VERSION 5.7 ;
  NOWIREEXTENSIONATPIN ON ;
  DIVIDERCHAR "/" ;
  BUSBITCHARS "[]" ;
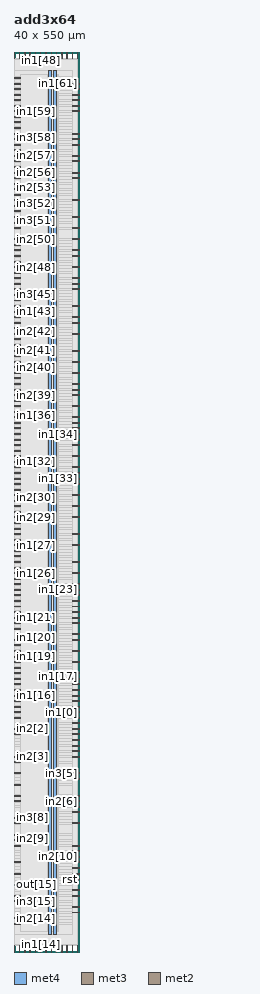
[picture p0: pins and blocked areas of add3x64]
MACRO add3x64
  CLASS BLOCK ;
  FOREIGN add3x64 ;
  ORIGIN 0.000 0.000 ;
  SIZE 40.000 BY 550.000 ;
  PIN VGND
    DIRECTION INOUT ;
    USE GROUND ;
    PORT
      LAYER met4 ;
        RECT 24.340 10.640 25.940 538.800 ;
    END
  END VGND
  PIN VPWR
    DIRECTION INOUT ;
    USE POWER ;
    PORT
      LAYER met4 ;
        RECT 21.040 10.640 22.640 538.800 ;
    END
  END VPWR
  PIN clk
    DIRECTION INPUT ;
    USE SIGNAL ;
    ANTENNAGATEAREA 1.286700 ;
    ANTENNADIFFAREA 0.434700 ;
    PORT
      LAYER met3 ;
        RECT 0.000 489.640 4.000 490.240 ;
    END
  END clk
  PIN in1[0]
    DIRECTION INPUT ;
    USE SIGNAL ;
    ANTENNAGATEAREA 0.631200 ;
    ANTENNADIFFAREA 0.434700 ;
    PORT
      LAYER met3 ;
        RECT 36.000 146.240 40.000 146.840 ;
    END
  END in1[0]
  PIN in1[10]
    DIRECTION INPUT ;
    USE SIGNAL ;
    ANTENNAGATEAREA 0.593700 ;
    ANTENNADIFFAREA 0.434700 ;
    PORT
      LAYER met2 ;
        RECT 19.410 0.000 19.690 4.000 ;
    END
  END in1[10]
  PIN in1[11]
    DIRECTION INPUT ;
    USE SIGNAL ;
    ANTENNAGATEAREA 0.631200 ;
    ANTENNADIFFAREA 0.434700 ;
    PORT
      LAYER met2 ;
        RECT 32.290 0.000 32.570 4.000 ;
    END
  END in1[11]
  PIN in1[12]
    DIRECTION INPUT ;
    USE SIGNAL ;
    ANTENNAGATEAREA 0.631200 ;
    ANTENNADIFFAREA 0.434700 ;
    PORT
      LAYER met2 ;
        RECT 38.730 0.000 39.010 4.000 ;
    END
  END in1[12]
  PIN in1[13]
    DIRECTION INPUT ;
    USE SIGNAL ;
    ANTENNAGATEAREA 0.560700 ;
    ANTENNADIFFAREA 0.434700 ;
    PORT
      LAYER met2 ;
        RECT 22.630 0.000 22.910 4.000 ;
    END
  END in1[13]
  PIN in1[14]
    DIRECTION INPUT ;
    USE SIGNAL ;
    ANTENNAGATEAREA 0.647700 ;
    ANTENNADIFFAREA 0.434700 ;
    PORT
      LAYER met2 ;
        RECT 16.190 0.000 16.470 4.000 ;
    END
  END in1[14]
  PIN in1[15]
    DIRECTION INPUT ;
    USE SIGNAL ;
    ANTENNAGATEAREA 0.560700 ;
    ANTENNADIFFAREA 0.434700 ;
    PORT
      LAYER met2 ;
        RECT 12.970 0.000 13.250 4.000 ;
    END
  END in1[15]
  PIN in1[16]
    DIRECTION INPUT ;
    USE SIGNAL ;
    ANTENNAGATEAREA 0.560700 ;
    ANTENNADIFFAREA 0.434700 ;
    PORT
      LAYER met3 ;
        RECT 0.000 156.440 4.000 157.040 ;
    END
  END in1[16]
  PIN in1[17]
    DIRECTION INPUT ;
    USE SIGNAL ;
    ANTENNAGATEAREA 0.647700 ;
    ANTENNADIFFAREA 0.434700 ;
    PORT
      LAYER met3 ;
        RECT 36.000 163.240 40.000 163.840 ;
    END
  END in1[17]
  PIN in1[18]
    DIRECTION INPUT ;
    USE SIGNAL ;
    ANTENNAGATEAREA 0.647700 ;
    ANTENNADIFFAREA 0.434700 ;
    PORT
      LAYER met3 ;
        RECT 0.000 170.040 4.000 170.640 ;
    END
  END in1[18]
  PIN in1[19]
    DIRECTION INPUT ;
    USE SIGNAL ;
    ANTENNAGATEAREA 0.560700 ;
    ANTENNADIFFAREA 0.434700 ;
    PORT
      LAYER met3 ;
        RECT 0.000 180.240 4.000 180.840 ;
    END
  END in1[19]
  PIN in1[1]
    DIRECTION INPUT ;
    USE SIGNAL ;
    ANTENNAGATEAREA 0.593700 ;
    ANTENNADIFFAREA 0.434700 ;
    PORT
      LAYER met3 ;
        RECT 0.000 146.240 4.000 146.840 ;
    END
  END in1[1]
  PIN in1[20]
    DIRECTION INPUT ;
    USE SIGNAL ;
    ANTENNAGATEAREA 0.647700 ;
    ANTENNADIFFAREA 0.434700 ;
    PORT
      LAYER met3 ;
        RECT 0.000 187.040 4.000 187.640 ;
    END
  END in1[20]
  PIN in1[21]
    DIRECTION INPUT ;
    USE SIGNAL ;
    ANTENNAGATEAREA 0.647700 ;
    ANTENNADIFFAREA 0.434700 ;
    PORT
      LAYER met3 ;
        RECT 0.000 204.040 4.000 204.640 ;
    END
  END in1[21]
  PIN in1[22]
    DIRECTION INPUT ;
    USE SIGNAL ;
    ANTENNAGATEAREA 0.560700 ;
    ANTENNADIFFAREA 0.434700 ;
    PORT
      LAYER met3 ;
        RECT 36.000 204.040 40.000 204.640 ;
    END
  END in1[22]
  PIN in1[23]
    DIRECTION INPUT ;
    USE SIGNAL ;
    ANTENNAGATEAREA 0.647700 ;
    ANTENNADIFFAREA 0.434700 ;
    PORT
      LAYER met3 ;
        RECT 36.000 221.040 40.000 221.640 ;
    END
  END in1[23]
  PIN in1[24]
    DIRECTION INPUT ;
    USE SIGNAL ;
    ANTENNAGATEAREA 0.631200 ;
    ANTENNADIFFAREA 0.434700 ;
    PORT
      LAYER met3 ;
        RECT 0.000 207.440 4.000 208.040 ;
    END
  END in1[24]
  PIN in1[25]
    DIRECTION INPUT ;
    USE SIGNAL ;
    ANTENNAGATEAREA 0.631200 ;
    ANTENNADIFFAREA 0.434700 ;
    PORT
      LAYER met3 ;
        RECT 0.000 221.040 4.000 221.640 ;
    END
  END in1[25]
  PIN in1[26]
    DIRECTION INPUT ;
    USE SIGNAL ;
    ANTENNAGATEAREA 0.647700 ;
    ANTENNADIFFAREA 0.434700 ;
    PORT
      LAYER met3 ;
        RECT 0.000 231.240 4.000 231.840 ;
    END
  END in1[26]
  PIN in1[27]
    DIRECTION INPUT ;
    USE SIGNAL ;
    ANTENNAGATEAREA 0.560700 ;
    ANTENNADIFFAREA 0.434700 ;
    PORT
      LAYER met3 ;
        RECT 0.000 248.240 4.000 248.840 ;
    END
  END in1[27]
  PIN in1[28]
    DIRECTION INPUT ;
    USE SIGNAL ;
    ANTENNAGATEAREA 0.560700 ;
    ANTENNADIFFAREA 0.434700 ;
    PORT
      LAYER met3 ;
        RECT 0.000 258.440 4.000 259.040 ;
    END
  END in1[28]
  PIN in1[29]
    DIRECTION INPUT ;
    USE SIGNAL ;
    ANTENNAGATEAREA 0.631200 ;
    ANTENNADIFFAREA 0.434700 ;
    PORT
      LAYER met3 ;
        RECT 0.000 261.840 4.000 262.440 ;
    END
  END in1[29]
  PIN in1[2]
    DIRECTION INPUT ;
    USE SIGNAL ;
    ANTENNAGATEAREA 0.647700 ;
    ANTENNADIFFAREA 0.434700 ;
    PORT
      LAYER met2 ;
        RECT 9.750 0.000 10.030 4.000 ;
    END
  END in1[2]
  PIN in1[30]
    DIRECTION INPUT ;
    USE SIGNAL ;
    ANTENNAGATEAREA 0.647700 ;
    ANTENNADIFFAREA 0.434700 ;
    PORT
      LAYER met3 ;
        RECT 0.000 285.640 4.000 286.240 ;
    END
  END in1[30]
  PIN in1[31]
    DIRECTION INPUT ;
    USE SIGNAL ;
    ANTENNAGATEAREA 0.631200 ;
    ANTENNADIFFAREA 0.434700 ;
    PORT
      LAYER met3 ;
        RECT 0.000 278.840 4.000 279.440 ;
    END
  END in1[31]
  PIN in1[32]
    DIRECTION INPUT ;
    USE SIGNAL ;
    ANTENNAGATEAREA 0.631200 ;
    ANTENNADIFFAREA 0.434700 ;
    PORT
      LAYER met3 ;
        RECT 0.000 299.240 4.000 299.840 ;
    END
  END in1[32]
  PIN in1[33]
    DIRECTION INPUT ;
    USE SIGNAL ;
    ANTENNAGATEAREA 0.631200 ;
    ANTENNADIFFAREA 0.434700 ;
    PORT
      LAYER met3 ;
        RECT 36.000 289.040 40.000 289.640 ;
    END
  END in1[33]
  PIN in1[34]
    DIRECTION INPUT ;
    USE SIGNAL ;
    ANTENNAGATEAREA 0.560700 ;
    ANTENNADIFFAREA 0.434700 ;
    PORT
      LAYER met3 ;
        RECT 36.000 316.240 40.000 316.840 ;
    END
  END in1[34]
  PIN in1[35]
    DIRECTION INPUT ;
    USE SIGNAL ;
    ANTENNAGATEAREA 0.647700 ;
    ANTENNADIFFAREA 0.434700 ;
    PORT
      LAYER met3 ;
        RECT 0.000 316.240 4.000 316.840 ;
    END
  END in1[35]
  PIN in1[36]
    DIRECTION INPUT ;
    USE SIGNAL ;
    ANTENNAGATEAREA 0.631200 ;
    ANTENNADIFFAREA 0.434700 ;
    PORT
      LAYER met3 ;
        RECT 0.000 323.040 4.000 323.640 ;
    END
  END in1[36]
  PIN in1[37]
    DIRECTION INPUT ;
    USE SIGNAL ;
    ANTENNAGATEAREA 0.631200 ;
    ANTENNADIFFAREA 0.434700 ;
    PORT
      LAYER met3 ;
        RECT 0.000 336.640 4.000 337.240 ;
    END
  END in1[37]
  PIN in1[38]
    DIRECTION INPUT ;
    USE SIGNAL ;
    ANTENNAGATEAREA 0.647700 ;
    ANTENNADIFFAREA 0.434700 ;
    PORT
      LAYER met3 ;
        RECT 36.000 346.840 40.000 347.440 ;
    END
  END in1[38]
  PIN in1[39]
    DIRECTION INPUT ;
    USE SIGNAL ;
    ANTENNAGATEAREA 0.631200 ;
    ANTENNADIFFAREA 0.434700 ;
    PORT
      LAYER met3 ;
        RECT 0.000 346.840 4.000 347.440 ;
    END
  END in1[39]
  PIN in1[3]
    DIRECTION INPUT ;
    USE SIGNAL ;
    ANTENNAGATEAREA 0.647700 ;
    ANTENNADIFFAREA 0.434700 ;
    PORT
      LAYER met2 ;
        RECT 0.090 0.000 0.370 4.000 ;
    END
  END in1[3]
  PIN in1[40]
    DIRECTION INPUT ;
    USE SIGNAL ;
    ANTENNAGATEAREA 0.631200 ;
    ANTENNADIFFAREA 0.434700 ;
    PORT
      LAYER met3 ;
        RECT 0.000 353.640 4.000 354.240 ;
    END
  END in1[40]
  PIN in1[41]
    DIRECTION INPUT ;
    USE SIGNAL ;
    ANTENNAGATEAREA 0.593700 ;
    ANTENNADIFFAREA 0.434700 ;
    PORT
      LAYER met3 ;
        RECT 0.000 363.840 4.000 364.440 ;
    END
  END in1[41]
  PIN in1[42]
    DIRECTION INPUT ;
    USE SIGNAL ;
    ANTENNAGATEAREA 0.631200 ;
    ANTENNADIFFAREA 0.434700 ;
    PORT
      LAYER met3 ;
        RECT 0.000 377.440 4.000 378.040 ;
    END
  END in1[42]
  PIN in1[43]
    DIRECTION INPUT ;
    USE SIGNAL ;
    ANTENNAGATEAREA 0.631200 ;
    ANTENNADIFFAREA 0.434700 ;
    PORT
      LAYER met3 ;
        RECT 0.000 391.040 4.000 391.640 ;
    END
  END in1[43]
  PIN in1[44]
    DIRECTION INPUT ;
    USE SIGNAL ;
    ANTENNAGATEAREA 0.631200 ;
    ANTENNADIFFAREA 0.434700 ;
    PORT
      LAYER met3 ;
        RECT 0.000 397.840 4.000 398.440 ;
    END
  END in1[44]
  PIN in1[45]
    DIRECTION INPUT ;
    USE SIGNAL ;
    ANTENNAGATEAREA 0.631200 ;
    ANTENNADIFFAREA 0.434700 ;
    PORT
      LAYER met3 ;
        RECT 0.000 411.440 4.000 412.040 ;
    END
  END in1[45]
  PIN in1[46]
    DIRECTION INPUT ;
    USE SIGNAL ;
    ANTENNAGATEAREA 0.593700 ;
    ANTENNADIFFAREA 0.434700 ;
    PORT
      LAYER met2 ;
        RECT 38.730 546.000 39.010 550.000 ;
    END
  END in1[46]
  PIN in1[47]
    DIRECTION INPUT ;
    USE SIGNAL ;
    ANTENNAGATEAREA 0.647700 ;
    ANTENNADIFFAREA 0.434700 ;
    PORT
      LAYER met2 ;
        RECT 32.290 546.000 32.570 550.000 ;
    END
  END in1[47]
  PIN in1[48]
    DIRECTION INPUT ;
    USE SIGNAL ;
    ANTENNAGATEAREA 0.647700 ;
    ANTENNADIFFAREA 0.434700 ;
    PORT
      LAYER met2 ;
        RECT 16.190 546.000 16.470 550.000 ;
    END
  END in1[48]
  PIN in1[49]
    DIRECTION INPUT ;
    USE SIGNAL ;
    ANTENNAGATEAREA 0.647700 ;
    ANTENNADIFFAREA 0.434700 ;
    PORT
      LAYER met2 ;
        RECT 35.510 546.000 35.790 550.000 ;
    END
  END in1[49]
  PIN in1[4]
    DIRECTION INPUT ;
    USE SIGNAL ;
    ANTENNAGATEAREA 0.647700 ;
    ANTENNADIFFAREA 0.434700 ;
    PORT
      LAYER met2 ;
        RECT 29.070 0.000 29.350 4.000 ;
    END
  END in1[4]
  PIN in1[50]
    DIRECTION INPUT ;
    USE SIGNAL ;
    ANTENNAGATEAREA 0.647700 ;
    ANTENNADIFFAREA 0.434700 ;
    PORT
      LAYER met2 ;
        RECT 12.970 546.000 13.250 550.000 ;
    END
  END in1[50]
  PIN in1[51]
    DIRECTION INPUT ;
    USE SIGNAL ;
    ANTENNAGATEAREA 0.647700 ;
    ANTENNADIFFAREA 0.434700 ;
    PORT
      LAYER met2 ;
        RECT 19.410 546.000 19.690 550.000 ;
    END
  END in1[51]
  PIN in1[52]
    DIRECTION INPUT ;
    USE SIGNAL ;
    ANTENNAGATEAREA 0.631200 ;
    ANTENNADIFFAREA 0.434700 ;
    PORT
      LAYER met2 ;
        RECT 9.750 546.000 10.030 550.000 ;
    END
  END in1[52]
  PIN in1[53]
    DIRECTION INPUT ;
    USE SIGNAL ;
    ANTENNAGATEAREA 0.560700 ;
    ANTENNADIFFAREA 0.434700 ;
    PORT
      LAYER met2 ;
        RECT 0.090 546.000 0.370 550.000 ;
    END
  END in1[53]
  PIN in1[54]
    DIRECTION INPUT ;
    USE SIGNAL ;
    ANTENNAGATEAREA 0.647700 ;
    ANTENNADIFFAREA 0.434700 ;
    PORT
      LAYER met2 ;
        RECT 25.850 546.000 26.130 550.000 ;
    END
  END in1[54]
  PIN in1[55]
    DIRECTION INPUT ;
    USE SIGNAL ;
    ANTENNAGATEAREA 0.631200 ;
    ANTENNADIFFAREA 0.434700 ;
    PORT
      LAYER met2 ;
        RECT 22.630 546.000 22.910 550.000 ;
    END
  END in1[55]
  PIN in1[56]
    DIRECTION INPUT ;
    USE SIGNAL ;
    ANTENNAGATEAREA 0.631200 ;
    ANTENNADIFFAREA 0.434700 ;
    PORT
      LAYER met2 ;
        RECT 3.310 546.000 3.590 550.000 ;
    END
  END in1[56]
  PIN in1[57]
    DIRECTION INPUT ;
    USE SIGNAL ;
    ANTENNAGATEAREA 0.631200 ;
    ANTENNADIFFAREA 0.434700 ;
    PORT
      LAYER met2 ;
        RECT 29.070 546.000 29.350 550.000 ;
    END
  END in1[57]
  PIN in1[58]
    DIRECTION INPUT ;
    USE SIGNAL ;
    ANTENNAGATEAREA 0.631200 ;
    ANTENNADIFFAREA 0.434700 ;
    PORT
      LAYER met2 ;
        RECT 6.530 546.000 6.810 550.000 ;
    END
  END in1[58]
  PIN in1[59]
    DIRECTION INPUT ;
    USE SIGNAL ;
    ANTENNAGATEAREA 0.631200 ;
    ANTENNADIFFAREA 0.434700 ;
    PORT
      LAYER met3 ;
        RECT 0.000 513.440 4.000 514.040 ;
    END
  END in1[59]
  PIN in1[5]
    DIRECTION INPUT ;
    USE SIGNAL ;
    ANTENNAGATEAREA 0.647700 ;
    ANTENNADIFFAREA 0.434700 ;
    PORT
      LAYER met2 ;
        RECT 35.510 0.000 35.790 4.000 ;
    END
  END in1[5]
  PIN in1[60]
    DIRECTION INPUT ;
    USE SIGNAL ;
    ANTENNAGATEAREA 0.631200 ;
    ANTENNADIFFAREA 0.434700 ;
    PORT
      LAYER met3 ;
        RECT 36.000 520.240 40.000 520.840 ;
    END
  END in1[60]
  PIN in1[61]
    DIRECTION INPUT ;
    USE SIGNAL ;
    ANTENNAGATEAREA 0.631200 ;
    ANTENNADIFFAREA 0.434700 ;
    PORT
      LAYER met3 ;
        RECT 36.000 530.440 40.000 531.040 ;
    END
  END in1[61]
  PIN in1[62]
    DIRECTION INPUT ;
    USE SIGNAL ;
    ANTENNAGATEAREA 0.631200 ;
    ANTENNADIFFAREA 0.434700 ;
    PORT
      LAYER met3 ;
        RECT 0.000 533.840 4.000 534.440 ;
    END
  END in1[62]
  PIN in1[63]
    DIRECTION INPUT ;
    USE SIGNAL ;
    ANTENNAGATEAREA 0.631200 ;
    ANTENNADIFFAREA 0.434700 ;
    PORT
      LAYER met3 ;
        RECT 0.000 523.640 4.000 524.240 ;
    END
  END in1[63]
  PIN in1[6]
    DIRECTION INPUT ;
    USE SIGNAL ;
    ANTENNAGATEAREA 0.647700 ;
    ANTENNADIFFAREA 0.434700 ;
    PORT
      LAYER met2 ;
        RECT 25.850 0.000 26.130 4.000 ;
    END
  END in1[6]
  PIN in1[7]
    DIRECTION INPUT ;
    USE SIGNAL ;
    ANTENNAGATEAREA 0.560700 ;
    ANTENNADIFFAREA 0.434700 ;
    PORT
      LAYER met2 ;
        RECT 3.310 0.000 3.590 4.000 ;
    END
  END in1[7]
  PIN in1[8]
    DIRECTION INPUT ;
    USE SIGNAL ;
    ANTENNAGATEAREA 0.560700 ;
    ANTENNADIFFAREA 0.434700 ;
    PORT
      LAYER met2 ;
        RECT 6.530 0.000 6.810 4.000 ;
    END
  END in1[8]
  PIN in1[9]
    DIRECTION INPUT ;
    USE SIGNAL ;
    ANTENNAGATEAREA 0.631200 ;
    ANTENNADIFFAREA 0.434700 ;
    PORT
      LAYER met3 ;
        RECT 0.000 71.440 4.000 72.040 ;
    END
  END in1[9]
  PIN in2[0]
    DIRECTION INPUT ;
    USE SIGNAL ;
    ANTENNAGATEAREA 0.631200 ;
    ANTENNADIFFAREA 0.434700 ;
    PORT
      LAYER met3 ;
        RECT 36.000 142.840 40.000 143.440 ;
    END
  END in2[0]
  PIN in2[10]
    DIRECTION INPUT ;
    USE SIGNAL ;
    ANTENNAGATEAREA 0.593700 ;
    ANTENNADIFFAREA 0.434700 ;
    PORT
      LAYER met3 ;
        RECT 36.000 57.840 40.000 58.440 ;
    END
  END in2[10]
  PIN in2[11]
    DIRECTION INPUT ;
    USE SIGNAL ;
    ANTENNAGATEAREA 0.631200 ;
    ANTENNADIFFAREA 0.434700 ;
    PORT
      LAYER met3 ;
        RECT 36.000 47.640 40.000 48.240 ;
    END
  END in2[11]
  PIN in2[12]
    DIRECTION INPUT ;
    USE SIGNAL ;
    ANTENNAGATEAREA 0.631200 ;
    ANTENNADIFFAREA 0.434700 ;
    PORT
      LAYER met3 ;
        RECT 36.000 37.440 40.000 38.040 ;
    END
  END in2[12]
  PIN in2[13]
    DIRECTION INPUT ;
    USE SIGNAL ;
    ANTENNAGATEAREA 0.560700 ;
    ANTENNADIFFAREA 0.434700 ;
    PORT
      LAYER met3 ;
        RECT 36.000 27.240 40.000 27.840 ;
    END
  END in2[13]
  PIN in2[14]
    DIRECTION INPUT ;
    USE SIGNAL ;
    ANTENNAGATEAREA 0.647700 ;
    ANTENNADIFFAREA 0.434700 ;
    PORT
      LAYER met3 ;
        RECT 0.000 20.440 4.000 21.040 ;
    END
  END in2[14]
  PIN in2[15]
    DIRECTION INPUT ;
    USE SIGNAL ;
    ANTENNAGATEAREA 0.560700 ;
    ANTENNADIFFAREA 0.434700 ;
    PORT
      LAYER met3 ;
        RECT 0.000 34.040 4.000 34.640 ;
    END
  END in2[15]
  PIN in2[16]
    DIRECTION INPUT ;
    USE SIGNAL ;
    ANTENNAGATEAREA 0.560700 ;
    ANTENNADIFFAREA 0.434700 ;
    PORT
      LAYER met3 ;
        RECT 0.000 159.840 4.000 160.440 ;
    END
  END in2[16]
  PIN in2[17]
    DIRECTION INPUT ;
    USE SIGNAL ;
    ANTENNAGATEAREA 0.647700 ;
    ANTENNADIFFAREA 0.434700 ;
    PORT
      LAYER met3 ;
        RECT 36.000 166.640 40.000 167.240 ;
    END
  END in2[17]
  PIN in2[18]
    DIRECTION INPUT ;
    USE SIGNAL ;
    ANTENNAGATEAREA 0.647700 ;
    ANTENNADIFFAREA 0.434700 ;
    PORT
      LAYER met3 ;
        RECT 0.000 166.640 4.000 167.240 ;
    END
  END in2[18]
  PIN in2[19]
    DIRECTION INPUT ;
    USE SIGNAL ;
    ANTENNAGATEAREA 0.560700 ;
    ANTENNADIFFAREA 0.434700 ;
    PORT
      LAYER met3 ;
        RECT 0.000 173.440 4.000 174.040 ;
    END
  END in2[19]
  PIN in2[1]
    DIRECTION INPUT ;
    USE SIGNAL ;
    ANTENNAGATEAREA 0.593700 ;
    ANTENNADIFFAREA 0.434700 ;
    PORT
      LAYER met3 ;
        RECT 0.000 142.840 4.000 143.440 ;
    END
  END in2[1]
  PIN in2[20]
    DIRECTION INPUT ;
    USE SIGNAL ;
    ANTENNAGATEAREA 0.647700 ;
    ANTENNADIFFAREA 0.434700 ;
    PORT
      LAYER met3 ;
        RECT 0.000 183.640 4.000 184.240 ;
    END
  END in2[20]
  PIN in2[21]
    DIRECTION INPUT ;
    USE SIGNAL ;
    ANTENNAGATEAREA 0.647700 ;
    ANTENNADIFFAREA 0.434700 ;
    PORT
      LAYER met3 ;
        RECT 0.000 197.240 4.000 197.840 ;
    END
  END in2[21]
  PIN in2[22]
    DIRECTION INPUT ;
    USE SIGNAL ;
    ANTENNAGATEAREA 0.560700 ;
    ANTENNADIFFAREA 0.434700 ;
    PORT
      LAYER met3 ;
        RECT 36.000 207.440 40.000 208.040 ;
    END
  END in2[22]
  PIN in2[23]
    DIRECTION INPUT ;
    USE SIGNAL ;
    ANTENNAGATEAREA 0.647700 ;
    ANTENNADIFFAREA 0.434700 ;
    PORT
      LAYER met3 ;
        RECT 36.000 217.640 40.000 218.240 ;
    END
  END in2[23]
  PIN in2[24]
    DIRECTION INPUT ;
    USE SIGNAL ;
    ANTENNAGATEAREA 0.631200 ;
    ANTENNADIFFAREA 0.434700 ;
    PORT
      LAYER met3 ;
        RECT 0.000 217.640 4.000 218.240 ;
    END
  END in2[24]
  PIN in2[25]
    DIRECTION INPUT ;
    USE SIGNAL ;
    ANTENNAGATEAREA 0.631200 ;
    ANTENNADIFFAREA 0.434700 ;
    PORT
      LAYER met3 ;
        RECT 0.000 227.840 4.000 228.440 ;
    END
  END in2[25]
  PIN in2[26]
    DIRECTION INPUT ;
    USE SIGNAL ;
    ANTENNAGATEAREA 0.647700 ;
    ANTENNADIFFAREA 0.434700 ;
    PORT
      LAYER met3 ;
        RECT 0.000 234.640 4.000 235.240 ;
    END
  END in2[26]
  PIN in2[27]
    DIRECTION INPUT ;
    USE SIGNAL ;
    ANTENNAGATEAREA 0.560700 ;
    ANTENNADIFFAREA 0.434700 ;
    PORT
      LAYER met3 ;
        RECT 0.000 244.840 4.000 245.440 ;
    END
  END in2[27]
  PIN in2[28]
    DIRECTION INPUT ;
    USE SIGNAL ;
    ANTENNAGATEAREA 0.631200 ;
    ANTENNADIFFAREA 0.434700 ;
    PORT
      LAYER met3 ;
        RECT 0.000 255.040 4.000 255.640 ;
    END
  END in2[28]
  PIN in2[29]
    DIRECTION INPUT ;
    USE SIGNAL ;
    ANTENNAGATEAREA 0.631200 ;
    ANTENNADIFFAREA 0.434700 ;
    PORT
      LAYER met3 ;
        RECT 0.000 265.240 4.000 265.840 ;
    END
  END in2[29]
  PIN in2[2]
    DIRECTION INPUT ;
    USE SIGNAL ;
    ANTENNAGATEAREA 0.631200 ;
    ANTENNADIFFAREA 0.434700 ;
    PORT
      LAYER met3 ;
        RECT 0.000 136.040 4.000 136.640 ;
    END
  END in2[2]
  PIN in2[30]
    DIRECTION INPUT ;
    USE SIGNAL ;
    ANTENNAGATEAREA 0.647700 ;
    ANTENNADIFFAREA 0.434700 ;
    PORT
      LAYER met3 ;
        RECT 0.000 282.240 4.000 282.840 ;
    END
  END in2[30]
  PIN in2[31]
    DIRECTION INPUT ;
    USE SIGNAL ;
    ANTENNAGATEAREA 0.631200 ;
    ANTENNADIFFAREA 0.434700 ;
    PORT
      LAYER met3 ;
        RECT 0.000 272.040 4.000 272.640 ;
    END
  END in2[31]
  PIN in2[32]
    DIRECTION INPUT ;
    USE SIGNAL ;
    ANTENNAGATEAREA 0.631200 ;
    ANTENNADIFFAREA 0.434700 ;
    PORT
      LAYER met3 ;
        RECT 0.000 292.440 4.000 293.040 ;
    END
  END in2[32]
  PIN in2[33]
    DIRECTION INPUT ;
    USE SIGNAL ;
    ANTENNAGATEAREA 0.631200 ;
    ANTENNADIFFAREA 0.434700 ;
    PORT
      LAYER met3 ;
        RECT 36.000 292.440 40.000 293.040 ;
    END
  END in2[33]
  PIN in2[34]
    DIRECTION INPUT ;
    USE SIGNAL ;
    ANTENNAGATEAREA 0.631200 ;
    ANTENNADIFFAREA 0.434700 ;
    PORT
      LAYER met3 ;
        RECT 36.000 309.440 40.000 310.040 ;
    END
  END in2[34]
  PIN in2[35]
    DIRECTION INPUT ;
    USE SIGNAL ;
    ANTENNAGATEAREA 0.647700 ;
    ANTENNADIFFAREA 0.434700 ;
    PORT
      LAYER met3 ;
        RECT 0.000 312.840 4.000 313.440 ;
    END
  END in2[35]
  PIN in2[36]
    DIRECTION INPUT ;
    USE SIGNAL ;
    ANTENNAGATEAREA 0.631200 ;
    ANTENNADIFFAREA 0.434700 ;
    PORT
      LAYER met3 ;
        RECT 0.000 326.440 4.000 327.040 ;
    END
  END in2[36]
  PIN in2[37]
    DIRECTION INPUT ;
    USE SIGNAL ;
    ANTENNAGATEAREA 0.631200 ;
    ANTENNADIFFAREA 0.434700 ;
    PORT
      LAYER met3 ;
        RECT 0.000 329.840 4.000 330.440 ;
    END
  END in2[37]
  PIN in2[38]
    DIRECTION INPUT ;
    USE SIGNAL ;
    ANTENNAGATEAREA 0.647700 ;
    ANTENNADIFFAREA 0.434700 ;
    PORT
      LAYER met3 ;
        RECT 36.000 343.440 40.000 344.040 ;
    END
  END in2[38]
  PIN in2[39]
    DIRECTION INPUT ;
    USE SIGNAL ;
    ANTENNAGATEAREA 0.631200 ;
    ANTENNADIFFAREA 0.434700 ;
    PORT
      LAYER met3 ;
        RECT 0.000 340.040 4.000 340.640 ;
    END
  END in2[39]
  PIN in2[3]
    DIRECTION INPUT ;
    USE SIGNAL ;
    ANTENNAGATEAREA 0.631200 ;
    ANTENNADIFFAREA 0.434700 ;
    PORT
      LAYER met3 ;
        RECT 0.000 119.040 4.000 119.640 ;
    END
  END in2[3]
  PIN in2[40]
    DIRECTION INPUT ;
    USE SIGNAL ;
    ANTENNAGATEAREA 0.631200 ;
    ANTENNADIFFAREA 0.434700 ;
    PORT
      LAYER met3 ;
        RECT 0.000 357.040 4.000 357.640 ;
    END
  END in2[40]
  PIN in2[41]
    DIRECTION INPUT ;
    USE SIGNAL ;
    ANTENNAGATEAREA 0.593700 ;
    ANTENNADIFFAREA 0.434700 ;
    PORT
      LAYER met3 ;
        RECT 0.000 367.240 4.000 367.840 ;
    END
  END in2[41]
  PIN in2[42]
    DIRECTION INPUT ;
    USE SIGNAL ;
    ANTENNAGATEAREA 0.631200 ;
    ANTENNADIFFAREA 0.434700 ;
    PORT
      LAYER met3 ;
        RECT 0.000 374.040 4.000 374.640 ;
    END
  END in2[42]
  PIN in2[43]
    DIRECTION INPUT ;
    USE SIGNAL ;
    ANTENNAGATEAREA 0.631200 ;
    ANTENNADIFFAREA 0.434700 ;
    PORT
      LAYER met3 ;
        RECT 0.000 384.240 4.000 384.840 ;
    END
  END in2[43]
  PIN in2[44]
    DIRECTION INPUT ;
    USE SIGNAL ;
    ANTENNAGATEAREA 0.631200 ;
    ANTENNADIFFAREA 0.434700 ;
    PORT
      LAYER met3 ;
        RECT 0.000 394.440 4.000 395.040 ;
    END
  END in2[44]
  PIN in2[45]
    DIRECTION INPUT ;
    USE SIGNAL ;
    ANTENNAGATEAREA 0.631200 ;
    ANTENNADIFFAREA 0.434700 ;
    PORT
      LAYER met3 ;
        RECT 0.000 404.640 4.000 405.240 ;
    END
  END in2[45]
  PIN in2[46]
    DIRECTION INPUT ;
    USE SIGNAL ;
    ANTENNAGATEAREA 0.560700 ;
    ANTENNADIFFAREA 0.434700 ;
    PORT
      LAYER met3 ;
        RECT 36.000 404.640 40.000 405.240 ;
    END
  END in2[46]
  PIN in2[47]
    DIRECTION INPUT ;
    USE SIGNAL ;
    ANTENNAGATEAREA 0.560700 ;
    ANTENNADIFFAREA 0.434700 ;
    PORT
      LAYER met3 ;
        RECT 0.000 421.640 4.000 422.240 ;
    END
  END in2[47]
  PIN in2[48]
    DIRECTION INPUT ;
    USE SIGNAL ;
    ANTENNAGATEAREA 0.631200 ;
    ANTENNADIFFAREA 0.434700 ;
    PORT
      LAYER met3 ;
        RECT 0.000 418.240 4.000 418.840 ;
    END
  END in2[48]
  PIN in2[49]
    DIRECTION INPUT ;
    USE SIGNAL ;
    ANTENNAGATEAREA 0.631200 ;
    ANTENNADIFFAREA 0.434700 ;
    PORT
      LAYER met3 ;
        RECT 0.000 428.440 4.000 429.040 ;
    END
  END in2[49]
  PIN in2[4]
    DIRECTION INPUT ;
    USE SIGNAL ;
    ANTENNAGATEAREA 0.631200 ;
    ANTENNADIFFAREA 0.434700 ;
    PORT
      LAYER met3 ;
        RECT 36.000 119.040 40.000 119.640 ;
    END
  END in2[4]
  PIN in2[50]
    DIRECTION INPUT ;
    USE SIGNAL ;
    ANTENNAGATEAREA 0.560700 ;
    ANTENNADIFFAREA 0.434700 ;
    PORT
      LAYER met3 ;
        RECT 0.000 435.240 4.000 435.840 ;
    END
  END in2[50]
  PIN in2[51]
    DIRECTION INPUT ;
    USE SIGNAL ;
    ANTENNAGATEAREA 0.647700 ;
    ANTENNADIFFAREA 0.434700 ;
    PORT
      LAYER met3 ;
        RECT 0.000 445.440 4.000 446.040 ;
    END
  END in2[51]
  PIN in2[52]
    DIRECTION INPUT ;
    USE SIGNAL ;
    ANTENNAGATEAREA 0.631200 ;
    ANTENNADIFFAREA 0.434700 ;
    PORT
      LAYER met3 ;
        RECT 0.000 448.840 4.000 449.440 ;
    END
  END in2[52]
  PIN in2[53]
    DIRECTION INPUT ;
    USE SIGNAL ;
    ANTENNAGATEAREA 0.631200 ;
    ANTENNADIFFAREA 0.434700 ;
    PORT
      LAYER met3 ;
        RECT 0.000 462.440 4.000 463.040 ;
    END
  END in2[53]
  PIN in2[54]
    DIRECTION INPUT ;
    USE SIGNAL ;
    ANTENNAGATEAREA 0.647700 ;
    ANTENNADIFFAREA 0.434700 ;
    PORT
      LAYER met3 ;
        RECT 0.000 465.840 4.000 466.440 ;
    END
  END in2[54]
  PIN in2[55]
    DIRECTION INPUT ;
    USE SIGNAL ;
    ANTENNAGATEAREA 0.631200 ;
    ANTENNADIFFAREA 0.434700 ;
    PORT
      LAYER met3 ;
        RECT 0.000 472.640 4.000 473.240 ;
    END
  END in2[55]
  PIN in2[56]
    DIRECTION INPUT ;
    USE SIGNAL ;
    ANTENNAGATEAREA 0.631200 ;
    ANTENNADIFFAREA 0.434700 ;
    PORT
      LAYER met3 ;
        RECT 0.000 476.040 4.000 476.640 ;
    END
  END in2[56]
  PIN in2[57]
    DIRECTION INPUT ;
    USE SIGNAL ;
    ANTENNAGATEAREA 0.631200 ;
    ANTENNADIFFAREA 0.434700 ;
    PORT
      LAYER met3 ;
        RECT 0.000 486.240 4.000 486.840 ;
    END
  END in2[57]
  PIN in2[58]
    DIRECTION INPUT ;
    USE SIGNAL ;
    ANTENNAGATEAREA 0.631200 ;
    ANTENNADIFFAREA 0.434700 ;
    PORT
      LAYER met3 ;
        RECT 0.000 496.440 4.000 497.040 ;
    END
  END in2[58]
  PIN in2[59]
    DIRECTION INPUT ;
    USE SIGNAL ;
    ANTENNAGATEAREA 0.631200 ;
    ANTENNADIFFAREA 0.434700 ;
    PORT
      LAYER met3 ;
        RECT 0.000 506.640 4.000 507.240 ;
    END
  END in2[59]
  PIN in2[5]
    DIRECTION INPUT ;
    USE SIGNAL ;
    ANTENNAGATEAREA 0.647700 ;
    ANTENNADIFFAREA 0.434700 ;
    PORT
      LAYER met3 ;
        RECT 36.000 105.440 40.000 106.040 ;
    END
  END in2[5]
  PIN in2[60]
    DIRECTION INPUT ;
    USE SIGNAL ;
    ANTENNAGATEAREA 0.631200 ;
    ANTENNADIFFAREA 0.434700 ;
    PORT
      LAYER met3 ;
        RECT 36.000 516.840 40.000 517.440 ;
    END
  END in2[60]
  PIN in2[61]
    DIRECTION INPUT ;
    USE SIGNAL ;
    ANTENNAGATEAREA 0.631200 ;
    ANTENNADIFFAREA 0.434700 ;
    PORT
      LAYER met3 ;
        RECT 36.000 523.640 40.000 524.240 ;
    END
  END in2[61]
  PIN in2[62]
    DIRECTION INPUT ;
    USE SIGNAL ;
    ANTENNAGATEAREA 0.631200 ;
    ANTENNADIFFAREA 0.434700 ;
    PORT
      LAYER met3 ;
        RECT 0.000 527.040 4.000 527.640 ;
    END
  END in2[62]
  PIN in2[63]
    DIRECTION INPUT ;
    USE SIGNAL ;
    ANTENNAGATEAREA 0.631200 ;
    ANTENNADIFFAREA 0.434700 ;
    PORT
      LAYER met3 ;
        RECT 0.000 516.840 4.000 517.440 ;
    END
  END in2[63]
  PIN in2[6]
    DIRECTION INPUT ;
    USE SIGNAL ;
    ANTENNAGATEAREA 0.560700 ;
    ANTENNADIFFAREA 0.434700 ;
    PORT
      LAYER met3 ;
        RECT 36.000 91.840 40.000 92.440 ;
    END
  END in2[6]
  PIN in2[7]
    DIRECTION INPUT ;
    USE SIGNAL ;
    ANTENNAGATEAREA 0.631200 ;
    ANTENNADIFFAREA 0.434700 ;
    PORT
      LAYER met3 ;
        RECT 0.000 91.840 4.000 92.440 ;
    END
  END in2[7]
  PIN in2[8]
    DIRECTION INPUT ;
    USE SIGNAL ;
    ANTENNAGATEAREA 0.631200 ;
    ANTENNADIFFAREA 0.434700 ;
    PORT
      LAYER met3 ;
        RECT 0.000 78.240 4.000 78.840 ;
    END
  END in2[8]
  PIN in2[9]
    DIRECTION INPUT ;
    USE SIGNAL ;
    ANTENNAGATEAREA 0.631200 ;
    ANTENNADIFFAREA 0.434700 ;
    PORT
      LAYER met3 ;
        RECT 0.000 64.640 4.000 65.240 ;
    END
  END in2[9]
  PIN in3[0]
    DIRECTION INPUT ;
    USE SIGNAL ;
    ANTENNAGATEAREA 0.631200 ;
    ANTENNADIFFAREA 0.434700 ;
    PORT
      LAYER met3 ;
        RECT 36.000 149.640 40.000 150.240 ;
    END
  END in3[0]
  PIN in3[10]
    DIRECTION INPUT ;
    USE SIGNAL ;
    ANTENNAGATEAREA 0.647700 ;
    ANTENNADIFFAREA 0.434700 ;
    PORT
      LAYER met3 ;
        RECT 36.000 61.240 40.000 61.840 ;
    END
  END in3[10]
  PIN in3[11]
    DIRECTION INPUT ;
    USE SIGNAL ;
    ANTENNAGATEAREA 0.631200 ;
    ANTENNADIFFAREA 0.434700 ;
    PORT
      LAYER met3 ;
        RECT 36.000 54.440 40.000 55.040 ;
    END
  END in3[11]
  PIN in3[12]
    DIRECTION INPUT ;
    USE SIGNAL ;
    ANTENNAGATEAREA 0.631200 ;
    ANTENNADIFFAREA 0.434700 ;
    PORT
      LAYER met3 ;
        RECT 36.000 34.040 40.000 34.640 ;
    END
  END in3[12]
  PIN in3[13]
    DIRECTION INPUT ;
    USE SIGNAL ;
    ANTENNAGATEAREA 0.631200 ;
    ANTENNADIFFAREA 0.434700 ;
    PORT
      LAYER met3 ;
        RECT 36.000 23.840 40.000 24.440 ;
    END
  END in3[13]
  PIN in3[14]
    DIRECTION INPUT ;
    USE SIGNAL ;
    ANTENNAGATEAREA 0.560700 ;
    ANTENNADIFFAREA 0.434700 ;
    PORT
      LAYER met3 ;
        RECT 0.000 17.040 4.000 17.640 ;
    END
  END in3[14]
  PIN in3[15]
    DIRECTION INPUT ;
    USE SIGNAL ;
    ANTENNAGATEAREA 0.631200 ;
    ANTENNADIFFAREA 0.434700 ;
    PORT
      LAYER met3 ;
        RECT 0.000 30.640 4.000 31.240 ;
    END
  END in3[15]
  PIN in3[16]
    DIRECTION INPUT ;
    USE SIGNAL ;
    ANTENNAGATEAREA 0.631200 ;
    ANTENNADIFFAREA 0.434700 ;
    PORT
      LAYER met3 ;
        RECT 0.000 163.240 4.000 163.840 ;
    END
  END in3[16]
  PIN in3[17]
    DIRECTION INPUT ;
    USE SIGNAL ;
    ANTENNAGATEAREA 0.631200 ;
    ANTENNADIFFAREA 0.434700 ;
    PORT
      LAYER met3 ;
        RECT 36.000 159.840 40.000 160.440 ;
    END
  END in3[17]
  PIN in3[18]
    DIRECTION INPUT ;
    USE SIGNAL ;
    ANTENNAGATEAREA 0.631200 ;
    ANTENNADIFFAREA 0.434700 ;
    PORT
      LAYER met3 ;
        RECT 36.000 170.040 40.000 170.640 ;
    END
  END in3[18]
  PIN in3[19]
    DIRECTION INPUT ;
    USE SIGNAL ;
    ANTENNAGATEAREA 0.631200 ;
    ANTENNADIFFAREA 0.434700 ;
    PORT
      LAYER met3 ;
        RECT 0.000 176.840 4.000 177.440 ;
    END
  END in3[19]
  PIN in3[1]
    DIRECTION INPUT ;
    USE SIGNAL ;
    ANTENNAGATEAREA 0.631200 ;
    ANTENNADIFFAREA 0.434700 ;
    PORT
      LAYER met3 ;
        RECT 0.000 149.640 4.000 150.240 ;
    END
  END in3[1]
  PIN in3[20]
    DIRECTION INPUT ;
    USE SIGNAL ;
    ANTENNAGATEAREA 0.631200 ;
    ANTENNADIFFAREA 0.434700 ;
    PORT
      LAYER met3 ;
        RECT 0.000 190.440 4.000 191.040 ;
    END
  END in3[20]
  PIN in3[21]
    DIRECTION INPUT ;
    USE SIGNAL ;
    ANTENNAGATEAREA 0.631200 ;
    ANTENNADIFFAREA 0.434700 ;
    PORT
      LAYER met3 ;
        RECT 0.000 200.640 4.000 201.240 ;
    END
  END in3[21]
  PIN in3[22]
    DIRECTION INPUT ;
    USE SIGNAL ;
    ANTENNAGATEAREA 0.631200 ;
    ANTENNADIFFAREA 0.434700 ;
    PORT
      LAYER met3 ;
        RECT 36.000 210.840 40.000 211.440 ;
    END
  END in3[22]
  PIN in3[23]
    DIRECTION INPUT ;
    USE SIGNAL ;
    ANTENNAGATEAREA 0.560700 ;
    ANTENNADIFFAREA 0.434700 ;
    PORT
      LAYER met3 ;
        RECT 36.000 214.240 40.000 214.840 ;
    END
  END in3[23]
  PIN in3[24]
    DIRECTION INPUT ;
    USE SIGNAL ;
    ANTENNAGATEAREA 0.631200 ;
    ANTENNADIFFAREA 0.434700 ;
    PORT
      LAYER met3 ;
        RECT 0.000 210.840 4.000 211.440 ;
    END
  END in3[24]
  PIN in3[25]
    DIRECTION INPUT ;
    USE SIGNAL ;
    ANTENNAGATEAREA 0.631200 ;
    ANTENNADIFFAREA 0.434700 ;
    PORT
      LAYER met3 ;
        RECT 0.000 224.440 4.000 225.040 ;
    END
  END in3[25]
  PIN in3[26]
    DIRECTION INPUT ;
    USE SIGNAL ;
    ANTENNAGATEAREA 0.631200 ;
    ANTENNADIFFAREA 0.434700 ;
    PORT
      LAYER met3 ;
        RECT 0.000 238.040 4.000 238.640 ;
    END
  END in3[26]
  PIN in3[27]
    DIRECTION INPUT ;
    USE SIGNAL ;
    ANTENNAGATEAREA 0.631200 ;
    ANTENNADIFFAREA 0.434700 ;
    PORT
      LAYER met3 ;
        RECT 0.000 241.440 4.000 242.040 ;
    END
  END in3[27]
  PIN in3[28]
    DIRECTION INPUT ;
    USE SIGNAL ;
    ANTENNAGATEAREA 0.631200 ;
    ANTENNADIFFAREA 0.434700 ;
    PORT
      LAYER met3 ;
        RECT 0.000 251.640 4.000 252.240 ;
    END
  END in3[28]
  PIN in3[29]
    DIRECTION INPUT ;
    USE SIGNAL ;
    ANTENNAGATEAREA 0.631200 ;
    ANTENNADIFFAREA 0.434700 ;
    PORT
      LAYER met3 ;
        RECT 0.000 268.640 4.000 269.240 ;
    END
  END in3[29]
  PIN in3[2]
    DIRECTION INPUT ;
    USE SIGNAL ;
    ANTENNAGATEAREA 0.631200 ;
    ANTENNADIFFAREA 0.434700 ;
    PORT
      LAYER met3 ;
        RECT 0.000 132.640 4.000 133.240 ;
    END
  END in3[2]
  PIN in3[30]
    DIRECTION INPUT ;
    USE SIGNAL ;
    ANTENNAGATEAREA 0.631200 ;
    ANTENNADIFFAREA 0.434700 ;
    PORT
      LAYER met3 ;
        RECT 0.000 295.840 4.000 296.440 ;
    END
  END in3[30]
  PIN in3[31]
    DIRECTION INPUT ;
    USE SIGNAL ;
    ANTENNAGATEAREA 0.631200 ;
    ANTENNADIFFAREA 0.434700 ;
    PORT
      LAYER met3 ;
        RECT 0.000 275.440 4.000 276.040 ;
    END
  END in3[31]
  PIN in3[32]
    DIRECTION INPUT ;
    USE SIGNAL ;
    ANTENNAGATEAREA 0.631200 ;
    ANTENNADIFFAREA 0.434700 ;
    PORT
      LAYER met3 ;
        RECT 0.000 289.040 4.000 289.640 ;
    END
  END in3[32]
  PIN in3[33]
    DIRECTION INPUT ;
    USE SIGNAL ;
    ANTENNAGATEAREA 0.631200 ;
    ANTENNADIFFAREA 0.434700 ;
    PORT
      LAYER met3 ;
        RECT 36.000 285.640 40.000 286.240 ;
    END
  END in3[33]
  PIN in3[34]
    DIRECTION INPUT ;
    USE SIGNAL ;
    ANTENNAGATEAREA 0.631200 ;
    ANTENNADIFFAREA 0.434700 ;
    PORT
      LAYER met3 ;
        RECT 36.000 312.840 40.000 313.440 ;
    END
  END in3[34]
  PIN in3[35]
    DIRECTION INPUT ;
    USE SIGNAL ;
    ANTENNAGATEAREA 0.631200 ;
    ANTENNADIFFAREA 0.434700 ;
    PORT
      LAYER met3 ;
        RECT 0.000 309.440 4.000 310.040 ;
    END
  END in3[35]
  PIN in3[36]
    DIRECTION INPUT ;
    USE SIGNAL ;
    ANTENNAGATEAREA 0.631200 ;
    ANTENNADIFFAREA 0.434700 ;
    PORT
      LAYER met3 ;
        RECT 0.000 319.640 4.000 320.240 ;
    END
  END in3[36]
  PIN in3[37]
    DIRECTION INPUT ;
    USE SIGNAL ;
    ANTENNAGATEAREA 0.631200 ;
    ANTENNADIFFAREA 0.434700 ;
    PORT
      LAYER met3 ;
        RECT 0.000 333.240 4.000 333.840 ;
    END
  END in3[37]
  PIN in3[38]
    DIRECTION INPUT ;
    USE SIGNAL ;
    ANTENNAGATEAREA 0.631200 ;
    ANTENNADIFFAREA 0.434700 ;
    PORT
      LAYER met3 ;
        RECT 36.000 340.040 40.000 340.640 ;
    END
  END in3[38]
  PIN in3[39]
    DIRECTION INPUT ;
    USE SIGNAL ;
    ANTENNAGATEAREA 0.631200 ;
    ANTENNADIFFAREA 0.434700 ;
    PORT
      LAYER met3 ;
        RECT 0.000 343.440 4.000 344.040 ;
    END
  END in3[39]
  PIN in3[3]
    DIRECTION INPUT ;
    USE SIGNAL ;
    ANTENNAGATEAREA 0.631200 ;
    ANTENNADIFFAREA 0.434700 ;
    PORT
      LAYER met3 ;
        RECT 0.000 115.640 4.000 116.240 ;
    END
  END in3[3]
  PIN in3[40]
    DIRECTION INPUT ;
    USE SIGNAL ;
    ANTENNAGATEAREA 0.631200 ;
    ANTENNADIFFAREA 0.434700 ;
    PORT
      LAYER met3 ;
        RECT 0.000 350.240 4.000 350.840 ;
    END
  END in3[40]
  PIN in3[41]
    DIRECTION INPUT ;
    USE SIGNAL ;
    ANTENNAGATEAREA 0.631200 ;
    ANTENNADIFFAREA 0.434700 ;
    PORT
      LAYER met3 ;
        RECT 0.000 360.440 4.000 361.040 ;
    END
  END in3[41]
  PIN in3[42]
    DIRECTION INPUT ;
    USE SIGNAL ;
    ANTENNAGATEAREA 0.631200 ;
    ANTENNADIFFAREA 0.434700 ;
    PORT
      LAYER met3 ;
        RECT 0.000 370.640 4.000 371.240 ;
    END
  END in3[42]
  PIN in3[43]
    DIRECTION INPUT ;
    USE SIGNAL ;
    ANTENNAGATEAREA 0.631200 ;
    ANTENNADIFFAREA 0.434700 ;
    PORT
      LAYER met3 ;
        RECT 0.000 380.840 4.000 381.440 ;
    END
  END in3[43]
  PIN in3[44]
    DIRECTION INPUT ;
    USE SIGNAL ;
    ANTENNAGATEAREA 0.631200 ;
    ANTENNADIFFAREA 0.434700 ;
    PORT
      LAYER met3 ;
        RECT 0.000 387.640 4.000 388.240 ;
    END
  END in3[44]
  PIN in3[45]
    DIRECTION INPUT ;
    USE SIGNAL ;
    ANTENNAGATEAREA 0.560700 ;
    ANTENNADIFFAREA 0.434700 ;
    PORT
      LAYER met3 ;
        RECT 0.000 401.240 4.000 401.840 ;
    END
  END in3[45]
  PIN in3[46]
    DIRECTION INPUT ;
    USE SIGNAL ;
    ANTENNAGATEAREA 0.631200 ;
    ANTENNADIFFAREA 0.434700 ;
    PORT
      LAYER met3 ;
        RECT 36.000 408.040 40.000 408.640 ;
    END
  END in3[46]
  PIN in3[47]
    DIRECTION INPUT ;
    USE SIGNAL ;
    ANTENNAGATEAREA 0.631200 ;
    ANTENNADIFFAREA 0.434700 ;
    PORT
      LAYER met3 ;
        RECT 0.000 408.040 4.000 408.640 ;
    END
  END in3[47]
  PIN in3[48]
    DIRECTION INPUT ;
    USE SIGNAL ;
    ANTENNAGATEAREA 0.631200 ;
    ANTENNADIFFAREA 0.434700 ;
    PORT
      LAYER met3 ;
        RECT 0.000 414.840 4.000 415.440 ;
    END
  END in3[48]
  PIN in3[49]
    DIRECTION INPUT ;
    USE SIGNAL ;
    ANTENNAGATEAREA 0.631200 ;
    ANTENNADIFFAREA 0.434700 ;
    PORT
      LAYER met3 ;
        RECT 0.000 425.040 4.000 425.640 ;
    END
  END in3[49]
  PIN in3[4]
    DIRECTION INPUT ;
    USE SIGNAL ;
    ANTENNAGATEAREA 0.647700 ;
    ANTENNADIFFAREA 0.434700 ;
    PORT
      LAYER met3 ;
        RECT 36.000 122.440 40.000 123.040 ;
    END
  END in3[4]
  PIN in3[50]
    DIRECTION INPUT ;
    USE SIGNAL ;
    ANTENNAGATEAREA 0.631200 ;
    ANTENNADIFFAREA 0.434700 ;
    PORT
      LAYER met3 ;
        RECT 0.000 431.840 4.000 432.440 ;
    END
  END in3[50]
  PIN in3[51]
    DIRECTION INPUT ;
    USE SIGNAL ;
    ANTENNAGATEAREA 0.631200 ;
    ANTENNADIFFAREA 0.434700 ;
    PORT
      LAYER met3 ;
        RECT 0.000 442.040 4.000 442.640 ;
    END
  END in3[51]
  PIN in3[52]
    DIRECTION INPUT ;
    USE SIGNAL ;
    ANTENNAGATEAREA 0.631200 ;
    ANTENNADIFFAREA 0.434700 ;
    PORT
      LAYER met3 ;
        RECT 0.000 452.240 4.000 452.840 ;
    END
  END in3[52]
  PIN in3[53]
    DIRECTION INPUT ;
    USE SIGNAL ;
    ANTENNAGATEAREA 0.631200 ;
    ANTENNADIFFAREA 0.434700 ;
    PORT
      LAYER met3 ;
        RECT 0.000 459.040 4.000 459.640 ;
    END
  END in3[53]
  PIN in3[54]
    DIRECTION INPUT ;
    USE SIGNAL ;
    ANTENNAGATEAREA 0.631200 ;
    ANTENNADIFFAREA 0.434700 ;
    PORT
      LAYER met3 ;
        RECT 0.000 455.640 4.000 456.240 ;
    END
  END in3[54]
  PIN in3[55]
    DIRECTION INPUT ;
    USE SIGNAL ;
    ANTENNAGATEAREA 0.631200 ;
    ANTENNADIFFAREA 0.434700 ;
    PORT
      LAYER met3 ;
        RECT 0.000 469.240 4.000 469.840 ;
    END
  END in3[55]
  PIN in3[56]
    DIRECTION INPUT ;
    USE SIGNAL ;
    ANTENNAGATEAREA 0.631200 ;
    ANTENNADIFFAREA 0.434700 ;
    PORT
      LAYER met3 ;
        RECT 0.000 479.440 4.000 480.040 ;
    END
  END in3[56]
  PIN in3[57]
    DIRECTION INPUT ;
    USE SIGNAL ;
    ANTENNAGATEAREA 0.631200 ;
    ANTENNADIFFAREA 0.434700 ;
    PORT
      LAYER met3 ;
        RECT 0.000 482.840 4.000 483.440 ;
    END
  END in3[57]
  PIN in3[58]
    DIRECTION INPUT ;
    USE SIGNAL ;
    ANTENNAGATEAREA 0.631200 ;
    ANTENNADIFFAREA 0.434700 ;
    PORT
      LAYER met3 ;
        RECT 0.000 493.040 4.000 493.640 ;
    END
  END in3[58]
  PIN in3[59]
    DIRECTION INPUT ;
    USE SIGNAL ;
    ANTENNAGATEAREA 0.631200 ;
    ANTENNADIFFAREA 0.434700 ;
    PORT
      LAYER met3 ;
        RECT 0.000 510.040 4.000 510.640 ;
    END
  END in3[59]
  PIN in3[5]
    DIRECTION INPUT ;
    USE SIGNAL ;
    ANTENNAGATEAREA 0.631200 ;
    ANTENNADIFFAREA 0.434700 ;
    PORT
      LAYER met3 ;
        RECT 36.000 108.840 40.000 109.440 ;
    END
  END in3[5]
  PIN in3[60]
    DIRECTION INPUT ;
    USE SIGNAL ;
    ANTENNAGATEAREA 0.631200 ;
    ANTENNADIFFAREA 0.434700 ;
    PORT
      LAYER met3 ;
        RECT 36.000 513.440 40.000 514.040 ;
    END
  END in3[60]
  PIN in3[61]
    DIRECTION INPUT ;
    USE SIGNAL ;
    ANTENNAGATEAREA 0.631200 ;
    ANTENNADIFFAREA 0.434700 ;
    PORT
      LAYER met3 ;
        RECT 36.000 527.040 40.000 527.640 ;
    END
  END in3[61]
  PIN in3[62]
    DIRECTION INPUT ;
    USE SIGNAL ;
    ANTENNAGATEAREA 0.631200 ;
    ANTENNADIFFAREA 0.434700 ;
    PORT
      LAYER met3 ;
        RECT 0.000 530.440 4.000 531.040 ;
    END
  END in3[62]
  PIN in3[63]
    DIRECTION INPUT ;
    USE SIGNAL ;
    ANTENNAGATEAREA 0.631200 ;
    ANTENNADIFFAREA 0.434700 ;
    PORT
      LAYER met3 ;
        RECT 0.000 520.240 4.000 520.840 ;
    END
  END in3[63]
  PIN in3[6]
    DIRECTION INPUT ;
    USE SIGNAL ;
    ANTENNAGATEAREA 0.560700 ;
    ANTENNADIFFAREA 0.434700 ;
    PORT
      LAYER met3 ;
        RECT 36.000 95.240 40.000 95.840 ;
    END
  END in3[6]
  PIN in3[7]
    DIRECTION INPUT ;
    USE SIGNAL ;
    ANTENNAGATEAREA 0.631200 ;
    ANTENNADIFFAREA 0.434700 ;
    PORT
      LAYER met3 ;
        RECT 0.000 95.240 4.000 95.840 ;
    END
  END in3[7]
  PIN in3[8]
    DIRECTION INPUT ;
    USE SIGNAL ;
    ANTENNAGATEAREA 0.631200 ;
    ANTENNADIFFAREA 0.434700 ;
    PORT
      LAYER met3 ;
        RECT 0.000 81.640 4.000 82.240 ;
    END
  END in3[8]
  PIN in3[9]
    DIRECTION INPUT ;
    USE SIGNAL ;
    ANTENNAGATEAREA 0.631200 ;
    ANTENNADIFFAREA 0.434700 ;
    PORT
      LAYER met3 ;
        RECT 0.000 68.040 4.000 68.640 ;
    END
  END in3[9]
  PIN out[0]
    DIRECTION OUTPUT ;
    USE SIGNAL ;
    ANTENNADIFFAREA 0.445500 ;
    PORT
      LAYER met3 ;
        RECT 36.000 153.040 40.000 153.640 ;
    END
  END out[0]
  PIN out[10]
    DIRECTION OUTPUT ;
    USE SIGNAL ;
    ANTENNADIFFAREA 0.445500 ;
    PORT
      LAYER met3 ;
        RECT 36.000 78.240 40.000 78.840 ;
    END
  END out[10]
  PIN out[11]
    DIRECTION OUTPUT ;
    USE SIGNAL ;
    ANTENNADIFFAREA 0.445500 ;
    PORT
      LAYER met3 ;
        RECT 36.000 64.640 40.000 65.240 ;
    END
  END out[11]
  PIN out[12]
    DIRECTION OUTPUT ;
    USE SIGNAL ;
    ANTENNADIFFAREA 0.445500 ;
    PORT
      LAYER met3 ;
        RECT 0.000 54.440 4.000 55.040 ;
    END
  END out[12]
  PIN out[13]
    DIRECTION OUTPUT ;
    USE SIGNAL ;
    ANTENNADIFFAREA 0.445500 ;
    PORT
      LAYER met3 ;
        RECT 0.000 47.640 4.000 48.240 ;
    END
  END out[13]
  PIN out[14]
    DIRECTION OUTPUT ;
    USE SIGNAL ;
    ANTENNADIFFAREA 0.445500 ;
    PORT
      LAYER met3 ;
        RECT 36.000 51.040 40.000 51.640 ;
    END
  END out[14]
  PIN out[15]
    DIRECTION OUTPUT ;
    USE SIGNAL ;
    ANTENNADIFFAREA 0.445500 ;
    PORT
      LAYER met3 ;
        RECT 0.000 40.840 4.000 41.440 ;
    END
  END out[15]
  PIN out[16]
    DIRECTION OUTPUT ;
    USE SIGNAL ;
    ANTENNADIFFAREA 0.445500 ;
    PORT
      LAYER met3 ;
        RECT 36.000 156.440 40.000 157.040 ;
    END
  END out[16]
  PIN out[17]
    DIRECTION OUTPUT ;
    USE SIGNAL ;
    ANTENNADIFFAREA 0.445500 ;
    PORT
      LAYER met3 ;
        RECT 0.000 153.040 4.000 153.640 ;
    END
  END out[17]
  PIN out[18]
    DIRECTION OUTPUT ;
    USE SIGNAL ;
    ANTENNADIFFAREA 0.445500 ;
    PORT
      LAYER met3 ;
        RECT 36.000 176.840 40.000 177.440 ;
    END
  END out[18]
  PIN out[19]
    DIRECTION OUTPUT ;
    USE SIGNAL ;
    ANTENNADIFFAREA 0.445500 ;
    PORT
      LAYER met3 ;
        RECT 36.000 183.640 40.000 184.240 ;
    END
  END out[19]
  PIN out[1]
    DIRECTION OUTPUT ;
    USE SIGNAL ;
    ANTENNADIFFAREA 0.445500 ;
    PORT
      LAYER met3 ;
        RECT 36.000 139.440 40.000 140.040 ;
    END
  END out[1]
  PIN out[20]
    DIRECTION OUTPUT ;
    USE SIGNAL ;
    ANTENNADIFFAREA 0.445500 ;
    PORT
      LAYER met3 ;
        RECT 36.000 190.440 40.000 191.040 ;
    END
  END out[20]
  PIN out[21]
    DIRECTION OUTPUT ;
    USE SIGNAL ;
    ANTENNADIFFAREA 0.445500 ;
    PORT
      LAYER met3 ;
        RECT 36.000 193.840 40.000 194.440 ;
    END
  END out[21]
  PIN out[22]
    DIRECTION OUTPUT ;
    USE SIGNAL ;
    ANTENNADIFFAREA 0.445500 ;
    PORT
      LAYER met3 ;
        RECT 36.000 200.640 40.000 201.240 ;
    END
  END out[22]
  PIN out[23]
    DIRECTION OUTPUT ;
    USE SIGNAL ;
    ANTENNADIFFAREA 0.445500 ;
    PORT
      LAYER met3 ;
        RECT 0.000 214.240 4.000 214.840 ;
    END
  END out[23]
  PIN out[24]
    DIRECTION OUTPUT ;
    USE SIGNAL ;
    ANTENNADIFFAREA 0.445500 ;
    PORT
      LAYER met3 ;
        RECT 36.000 224.440 40.000 225.040 ;
    END
  END out[24]
  PIN out[25]
    DIRECTION OUTPUT ;
    USE SIGNAL ;
    ANTENNADIFFAREA 0.445500 ;
    PORT
      LAYER met3 ;
        RECT 36.000 231.240 40.000 231.840 ;
    END
  END out[25]
  PIN out[26]
    DIRECTION OUTPUT ;
    USE SIGNAL ;
    ANTENNADIFFAREA 0.445500 ;
    PORT
      LAYER met3 ;
        RECT 36.000 238.040 40.000 238.640 ;
    END
  END out[26]
  PIN out[27]
    DIRECTION OUTPUT ;
    USE SIGNAL ;
    ANTENNADIFFAREA 0.445500 ;
    PORT
      LAYER met3 ;
        RECT 36.000 248.240 40.000 248.840 ;
    END
  END out[27]
  PIN out[28]
    DIRECTION OUTPUT ;
    USE SIGNAL ;
    ANTENNADIFFAREA 0.445500 ;
    PORT
      LAYER met3 ;
        RECT 36.000 255.040 40.000 255.640 ;
    END
  END out[28]
  PIN out[29]
    DIRECTION OUTPUT ;
    USE SIGNAL ;
    ANTENNADIFFAREA 0.445500 ;
    PORT
      LAYER met3 ;
        RECT 36.000 265.240 40.000 265.840 ;
    END
  END out[29]
  PIN out[2]
    DIRECTION OUTPUT ;
    USE SIGNAL ;
    ANTENNADIFFAREA 0.445500 ;
    PORT
      LAYER met3 ;
        RECT 36.000 132.640 40.000 133.240 ;
    END
  END out[2]
  PIN out[30]
    DIRECTION OUTPUT ;
    USE SIGNAL ;
    ANTENNADIFFAREA 0.445500 ;
    PORT
      LAYER met3 ;
        RECT 36.000 272.040 40.000 272.640 ;
    END
  END out[30]
  PIN out[31]
    DIRECTION OUTPUT ;
    USE SIGNAL ;
    ANTENNADIFFAREA 0.445500 ;
    PORT
      LAYER met3 ;
        RECT 36.000 278.840 40.000 279.440 ;
    END
  END out[31]
  PIN out[32]
    DIRECTION OUTPUT ;
    USE SIGNAL ;
    ANTENNADIFFAREA 0.445500 ;
    PORT
      LAYER met3 ;
        RECT 0.000 302.640 4.000 303.240 ;
    END
  END out[32]
  PIN out[33]
    DIRECTION OUTPUT ;
    USE SIGNAL ;
    ANTENNADIFFAREA 0.445500 ;
    PORT
      LAYER met3 ;
        RECT 36.000 295.840 40.000 296.440 ;
    END
  END out[33]
  PIN out[34]
    DIRECTION OUTPUT ;
    USE SIGNAL ;
    ANTENNADIFFAREA 0.445500 ;
    PORT
      LAYER met3 ;
        RECT 36.000 302.640 40.000 303.240 ;
    END
  END out[34]
  PIN out[35]
    DIRECTION OUTPUT ;
    USE SIGNAL ;
    ANTENNADIFFAREA 0.445500 ;
    PORT
      LAYER met3 ;
        RECT 0.000 306.040 4.000 306.640 ;
    END
  END out[35]
  PIN out[36]
    DIRECTION OUTPUT ;
    USE SIGNAL ;
    ANTENNADIFFAREA 0.445500 ;
    PORT
      LAYER met3 ;
        RECT 36.000 319.640 40.000 320.240 ;
    END
  END out[36]
  PIN out[37]
    DIRECTION OUTPUT ;
    USE SIGNAL ;
    ANTENNADIFFAREA 0.445500 ;
    PORT
      LAYER met3 ;
        RECT 36.000 323.040 40.000 323.640 ;
    END
  END out[37]
  PIN out[38]
    DIRECTION OUTPUT ;
    USE SIGNAL ;
    ANTENNADIFFAREA 0.445500 ;
    PORT
      LAYER met3 ;
        RECT 36.000 326.440 40.000 327.040 ;
    END
  END out[38]
  PIN out[39]
    DIRECTION OUTPUT ;
    USE SIGNAL ;
    ANTENNADIFFAREA 0.445500 ;
    PORT
      LAYER met3 ;
        RECT 36.000 333.240 40.000 333.840 ;
    END
  END out[39]
  PIN out[3]
    DIRECTION OUTPUT ;
    USE SIGNAL ;
    ANTENNADIFFAREA 0.445500 ;
    PORT
      LAYER met3 ;
        RECT 36.000 136.040 40.000 136.640 ;
    END
  END out[3]
  PIN out[40]
    DIRECTION OUTPUT ;
    USE SIGNAL ;
    ANTENNADIFFAREA 0.445500 ;
    PORT
      LAYER met3 ;
        RECT 36.000 353.640 40.000 354.240 ;
    END
  END out[40]
  PIN out[41]
    DIRECTION OUTPUT ;
    USE SIGNAL ;
    ANTENNADIFFAREA 0.445500 ;
    PORT
      LAYER met3 ;
        RECT 36.000 360.440 40.000 361.040 ;
    END
  END out[41]
  PIN out[42]
    DIRECTION OUTPUT ;
    USE SIGNAL ;
    ANTENNADIFFAREA 0.445500 ;
    PORT
      LAYER met3 ;
        RECT 36.000 367.240 40.000 367.840 ;
    END
  END out[42]
  PIN out[43]
    DIRECTION OUTPUT ;
    USE SIGNAL ;
    ANTENNADIFFAREA 0.445500 ;
    PORT
      LAYER met3 ;
        RECT 36.000 377.440 40.000 378.040 ;
    END
  END out[43]
  PIN out[44]
    DIRECTION OUTPUT ;
    USE SIGNAL ;
    ANTENNADIFFAREA 0.445500 ;
    PORT
      LAYER met3 ;
        RECT 36.000 384.240 40.000 384.840 ;
    END
  END out[44]
  PIN out[45]
    DIRECTION OUTPUT ;
    USE SIGNAL ;
    ANTENNADIFFAREA 0.445500 ;
    PORT
      LAYER met3 ;
        RECT 36.000 387.640 40.000 388.240 ;
    END
  END out[45]
  PIN out[46]
    DIRECTION OUTPUT ;
    USE SIGNAL ;
    ANTENNADIFFAREA 0.445500 ;
    PORT
      LAYER met3 ;
        RECT 36.000 394.440 40.000 395.040 ;
    END
  END out[46]
  PIN out[47]
    DIRECTION OUTPUT ;
    USE SIGNAL ;
    ANTENNADIFFAREA 0.445500 ;
    PORT
      LAYER met3 ;
        RECT 36.000 411.440 40.000 412.040 ;
    END
  END out[47]
  PIN out[48]
    DIRECTION OUTPUT ;
    USE SIGNAL ;
    ANTENNADIFFAREA 0.445500 ;
    PORT
      LAYER met3 ;
        RECT 36.000 418.240 40.000 418.840 ;
    END
  END out[48]
  PIN out[49]
    DIRECTION OUTPUT ;
    USE SIGNAL ;
    ANTENNADIFFAREA 0.445500 ;
    PORT
      LAYER met3 ;
        RECT 36.000 425.040 40.000 425.640 ;
    END
  END out[49]
  PIN out[4]
    DIRECTION OUTPUT ;
    USE SIGNAL ;
    ANTENNADIFFAREA 0.445500 ;
    PORT
      LAYER met3 ;
        RECT 36.000 125.840 40.000 126.440 ;
    END
  END out[4]
  PIN out[50]
    DIRECTION OUTPUT ;
    USE SIGNAL ;
    ANTENNADIFFAREA 0.445500 ;
    PORT
      LAYER met3 ;
        RECT 36.000 428.440 40.000 429.040 ;
    END
  END out[50]
  PIN out[51]
    DIRECTION OUTPUT ;
    USE SIGNAL ;
    ANTENNADIFFAREA 0.445500 ;
    PORT
      LAYER met3 ;
        RECT 36.000 435.240 40.000 435.840 ;
    END
  END out[51]
  PIN out[52]
    DIRECTION OUTPUT ;
    USE SIGNAL ;
    ANTENNADIFFAREA 0.445500 ;
    PORT
      LAYER met3 ;
        RECT 36.000 442.040 40.000 442.640 ;
    END
  END out[52]
  PIN out[53]
    DIRECTION OUTPUT ;
    USE SIGNAL ;
    ANTENNADIFFAREA 0.445500 ;
    PORT
      LAYER met3 ;
        RECT 36.000 448.840 40.000 449.440 ;
    END
  END out[53]
  PIN out[54]
    DIRECTION OUTPUT ;
    USE SIGNAL ;
    ANTENNADIFFAREA 0.445500 ;
    PORT
      LAYER met3 ;
        RECT 36.000 459.040 40.000 459.640 ;
    END
  END out[54]
  PIN out[55]
    DIRECTION OUTPUT ;
    USE SIGNAL ;
    ANTENNADIFFAREA 0.445500 ;
    PORT
      LAYER met3 ;
        RECT 36.000 472.640 40.000 473.240 ;
    END
  END out[55]
  PIN out[56]
    DIRECTION OUTPUT ;
    USE SIGNAL ;
    ANTENNADIFFAREA 0.445500 ;
    PORT
      LAYER met3 ;
        RECT 36.000 476.040 40.000 476.640 ;
    END
  END out[56]
  PIN out[57]
    DIRECTION OUTPUT ;
    USE SIGNAL ;
    ANTENNADIFFAREA 0.445500 ;
    PORT
      LAYER met3 ;
        RECT 36.000 482.840 40.000 483.440 ;
    END
  END out[57]
  PIN out[58]
    DIRECTION OUTPUT ;
    USE SIGNAL ;
    ANTENNADIFFAREA 0.445500 ;
    PORT
      LAYER met3 ;
        RECT 36.000 486.240 40.000 486.840 ;
    END
  END out[58]
  PIN out[59]
    DIRECTION OUTPUT ;
    USE SIGNAL ;
    ANTENNADIFFAREA 0.445500 ;
    PORT
      LAYER met3 ;
        RECT 36.000 496.440 40.000 497.040 ;
    END
  END out[59]
  PIN out[5]
    DIRECTION OUTPUT ;
    USE SIGNAL ;
    ANTENNADIFFAREA 0.445500 ;
    PORT
      LAYER met3 ;
        RECT 36.000 129.240 40.000 129.840 ;
    END
  END out[5]
  PIN out[60]
    DIRECTION OUTPUT ;
    USE SIGNAL ;
    ANTENNADIFFAREA 0.445500 ;
    PORT
      LAYER met3 ;
        RECT 36.000 493.040 40.000 493.640 ;
    END
  END out[60]
  PIN out[61]
    DIRECTION OUTPUT ;
    USE SIGNAL ;
    ANTENNADIFFAREA 0.445500 ;
    PORT
      LAYER met3 ;
        RECT 36.000 499.840 40.000 500.440 ;
    END
  END out[61]
  PIN out[62]
    DIRECTION OUTPUT ;
    USE SIGNAL ;
    ANTENNADIFFAREA 0.445500 ;
    PORT
      LAYER met3 ;
        RECT 0.000 499.840 4.000 500.440 ;
    END
  END out[62]
  PIN out[63]
    DIRECTION OUTPUT ;
    USE SIGNAL ;
    ANTENNADIFFAREA 0.445500 ;
    PORT
      LAYER met3 ;
        RECT 0.000 503.240 4.000 503.840 ;
    END
  END out[63]
  PIN out[6]
    DIRECTION OUTPUT ;
    USE SIGNAL ;
    ANTENNADIFFAREA 0.445500 ;
    PORT
      LAYER met3 ;
        RECT 0.000 108.840 4.000 109.440 ;
    END
  END out[6]
  PIN out[7]
    DIRECTION OUTPUT ;
    USE SIGNAL ;
    ANTENNADIFFAREA 0.445500 ;
    PORT
      LAYER met3 ;
        RECT 0.000 102.040 4.000 102.640 ;
    END
  END out[7]
  PIN out[8]
    DIRECTION OUTPUT ;
    USE SIGNAL ;
    ANTENNADIFFAREA 0.445500 ;
    PORT
      LAYER met3 ;
        RECT 36.000 88.440 40.000 89.040 ;
    END
  END out[8]
  PIN out[9]
    DIRECTION OUTPUT ;
    USE SIGNAL ;
    ANTENNADIFFAREA 0.445500 ;
    PORT
      LAYER met3 ;
        RECT 36.000 85.040 40.000 85.640 ;
    END
  END out[9]
  PIN rst
    DIRECTION INPUT ;
    USE SIGNAL ;
    ANTENNAGATEAREA 0.631200 ;
    ANTENNADIFFAREA 0.434700 ;
    PORT
      LAYER met3 ;
        RECT 36.000 44.240 40.000 44.840 ;
    END
  END rst
  OBS
      LAYER nwell ;
        RECT 5.330 10.795 34.230 538.645 ;
      LAYER li1 ;
        RECT 5.520 10.795 34.040 538.645 ;
      LAYER met1 ;
        RECT 0.070 6.160 39.030 538.800 ;
      LAYER met2 ;
        RECT 0.650 545.720 3.030 546.000 ;
        RECT 3.870 545.720 6.250 546.000 ;
        RECT 7.090 545.720 9.470 546.000 ;
        RECT 10.310 545.720 12.690 546.000 ;
        RECT 13.530 545.720 15.910 546.000 ;
        RECT 16.750 545.720 19.130 546.000 ;
        RECT 19.970 545.720 22.350 546.000 ;
        RECT 23.190 545.720 25.570 546.000 ;
        RECT 26.410 545.720 28.790 546.000 ;
        RECT 29.630 545.720 32.010 546.000 ;
        RECT 32.850 545.720 35.230 546.000 ;
        RECT 36.070 545.720 38.450 546.000 ;
        RECT 0.100 4.280 39.000 545.720 ;
        RECT 0.650 4.000 3.030 4.280 ;
        RECT 3.870 4.000 6.250 4.280 ;
        RECT 7.090 4.000 9.470 4.280 ;
        RECT 10.310 4.000 12.690 4.280 ;
        RECT 13.530 4.000 15.910 4.280 ;
        RECT 16.750 4.000 19.130 4.280 ;
        RECT 19.970 4.000 22.350 4.280 ;
        RECT 23.190 4.000 25.570 4.280 ;
        RECT 26.410 4.000 28.790 4.280 ;
        RECT 29.630 4.000 32.010 4.280 ;
        RECT 32.850 4.000 35.230 4.280 ;
        RECT 36.070 4.000 38.450 4.280 ;
      LAYER met3 ;
        RECT 0.525 534.840 36.000 538.725 ;
        RECT 4.400 533.440 36.000 534.840 ;
        RECT 0.525 531.440 36.000 533.440 ;
        RECT 4.400 530.040 35.600 531.440 ;
        RECT 0.525 528.040 36.000 530.040 ;
        RECT 4.400 526.640 35.600 528.040 ;
        RECT 0.525 524.640 36.000 526.640 ;
        RECT 4.400 523.240 35.600 524.640 ;
        RECT 0.525 521.240 36.000 523.240 ;
        RECT 4.400 519.840 35.600 521.240 ;
        RECT 0.525 517.840 36.000 519.840 ;
        RECT 4.400 516.440 35.600 517.840 ;
        RECT 0.525 514.440 36.000 516.440 ;
        RECT 4.400 513.040 35.600 514.440 ;
        RECT 0.525 511.040 36.000 513.040 ;
        RECT 4.400 509.640 36.000 511.040 ;
        RECT 0.525 507.640 36.000 509.640 ;
        RECT 4.400 506.240 36.000 507.640 ;
        RECT 0.525 504.240 36.000 506.240 ;
        RECT 4.400 502.840 36.000 504.240 ;
        RECT 0.525 500.840 36.000 502.840 ;
        RECT 4.400 499.440 35.600 500.840 ;
        RECT 0.525 497.440 36.000 499.440 ;
        RECT 4.400 496.040 35.600 497.440 ;
        RECT 0.525 494.040 36.000 496.040 ;
        RECT 4.400 492.640 35.600 494.040 ;
        RECT 0.525 490.640 36.000 492.640 ;
        RECT 4.400 489.240 36.000 490.640 ;
        RECT 0.525 487.240 36.000 489.240 ;
        RECT 4.400 485.840 35.600 487.240 ;
        RECT 0.525 483.840 36.000 485.840 ;
        RECT 4.400 482.440 35.600 483.840 ;
        RECT 0.525 480.440 36.000 482.440 ;
        RECT 4.400 479.040 36.000 480.440 ;
        RECT 0.525 477.040 36.000 479.040 ;
        RECT 4.400 475.640 35.600 477.040 ;
        RECT 0.525 473.640 36.000 475.640 ;
        RECT 4.400 472.240 35.600 473.640 ;
        RECT 0.525 470.240 36.000 472.240 ;
        RECT 4.400 468.840 36.000 470.240 ;
        RECT 0.525 466.840 36.000 468.840 ;
        RECT 4.400 465.440 36.000 466.840 ;
        RECT 0.525 463.440 36.000 465.440 ;
        RECT 4.400 462.040 36.000 463.440 ;
        RECT 0.525 460.040 36.000 462.040 ;
        RECT 4.400 458.640 35.600 460.040 ;
        RECT 0.525 456.640 36.000 458.640 ;
        RECT 4.400 455.240 36.000 456.640 ;
        RECT 0.525 453.240 36.000 455.240 ;
        RECT 4.400 451.840 36.000 453.240 ;
        RECT 0.525 449.840 36.000 451.840 ;
        RECT 4.400 448.440 35.600 449.840 ;
        RECT 0.525 446.440 36.000 448.440 ;
        RECT 4.400 445.040 36.000 446.440 ;
        RECT 0.525 443.040 36.000 445.040 ;
        RECT 4.400 441.640 35.600 443.040 ;
        RECT 0.525 436.240 36.000 441.640 ;
        RECT 4.400 434.840 35.600 436.240 ;
        RECT 0.525 432.840 36.000 434.840 ;
        RECT 4.400 431.440 36.000 432.840 ;
        RECT 0.525 429.440 36.000 431.440 ;
        RECT 4.400 428.040 35.600 429.440 ;
        RECT 0.525 426.040 36.000 428.040 ;
        RECT 4.400 424.640 35.600 426.040 ;
        RECT 0.525 422.640 36.000 424.640 ;
        RECT 4.400 421.240 36.000 422.640 ;
        RECT 0.525 419.240 36.000 421.240 ;
        RECT 4.400 417.840 35.600 419.240 ;
        RECT 0.525 415.840 36.000 417.840 ;
        RECT 4.400 414.440 36.000 415.840 ;
        RECT 0.525 412.440 36.000 414.440 ;
        RECT 4.400 411.040 35.600 412.440 ;
        RECT 0.525 409.040 36.000 411.040 ;
        RECT 4.400 407.640 35.600 409.040 ;
        RECT 0.525 405.640 36.000 407.640 ;
        RECT 4.400 404.240 35.600 405.640 ;
        RECT 0.525 402.240 36.000 404.240 ;
        RECT 4.400 400.840 36.000 402.240 ;
        RECT 0.525 398.840 36.000 400.840 ;
        RECT 4.400 397.440 36.000 398.840 ;
        RECT 0.525 395.440 36.000 397.440 ;
        RECT 4.400 394.040 35.600 395.440 ;
        RECT 0.525 392.040 36.000 394.040 ;
        RECT 4.400 390.640 36.000 392.040 ;
        RECT 0.525 388.640 36.000 390.640 ;
        RECT 4.400 387.240 35.600 388.640 ;
        RECT 0.525 385.240 36.000 387.240 ;
        RECT 4.400 383.840 35.600 385.240 ;
        RECT 0.525 381.840 36.000 383.840 ;
        RECT 4.400 380.440 36.000 381.840 ;
        RECT 0.525 378.440 36.000 380.440 ;
        RECT 4.400 377.040 35.600 378.440 ;
        RECT 0.525 375.040 36.000 377.040 ;
        RECT 4.400 373.640 36.000 375.040 ;
        RECT 0.525 371.640 36.000 373.640 ;
        RECT 4.400 370.240 36.000 371.640 ;
        RECT 0.525 368.240 36.000 370.240 ;
        RECT 4.400 366.840 35.600 368.240 ;
        RECT 0.525 364.840 36.000 366.840 ;
        RECT 4.400 363.440 36.000 364.840 ;
        RECT 0.525 361.440 36.000 363.440 ;
        RECT 4.400 360.040 35.600 361.440 ;
        RECT 0.525 358.040 36.000 360.040 ;
        RECT 4.400 356.640 36.000 358.040 ;
        RECT 0.525 354.640 36.000 356.640 ;
        RECT 4.400 353.240 35.600 354.640 ;
        RECT 0.525 351.240 36.000 353.240 ;
        RECT 4.400 349.840 36.000 351.240 ;
        RECT 0.525 347.840 36.000 349.840 ;
        RECT 4.400 346.440 35.600 347.840 ;
        RECT 0.525 344.440 36.000 346.440 ;
        RECT 4.400 343.040 35.600 344.440 ;
        RECT 0.525 341.040 36.000 343.040 ;
        RECT 4.400 339.640 35.600 341.040 ;
        RECT 0.525 337.640 36.000 339.640 ;
        RECT 4.400 336.240 36.000 337.640 ;
        RECT 0.525 334.240 36.000 336.240 ;
        RECT 4.400 332.840 35.600 334.240 ;
        RECT 0.525 330.840 36.000 332.840 ;
        RECT 4.400 329.440 36.000 330.840 ;
        RECT 0.525 327.440 36.000 329.440 ;
        RECT 4.400 326.040 35.600 327.440 ;
        RECT 0.525 324.040 36.000 326.040 ;
        RECT 4.400 322.640 35.600 324.040 ;
        RECT 0.525 320.640 36.000 322.640 ;
        RECT 4.400 319.240 35.600 320.640 ;
        RECT 0.525 317.240 36.000 319.240 ;
        RECT 4.400 315.840 35.600 317.240 ;
        RECT 0.525 313.840 36.000 315.840 ;
        RECT 4.400 312.440 35.600 313.840 ;
        RECT 0.525 310.440 36.000 312.440 ;
        RECT 4.400 309.040 35.600 310.440 ;
        RECT 0.525 307.040 36.000 309.040 ;
        RECT 4.400 305.640 36.000 307.040 ;
        RECT 0.525 303.640 36.000 305.640 ;
        RECT 4.400 302.240 35.600 303.640 ;
        RECT 0.525 300.240 36.000 302.240 ;
        RECT 4.400 298.840 36.000 300.240 ;
        RECT 0.525 296.840 36.000 298.840 ;
        RECT 4.400 295.440 35.600 296.840 ;
        RECT 0.525 293.440 36.000 295.440 ;
        RECT 4.400 292.040 35.600 293.440 ;
        RECT 0.525 290.040 36.000 292.040 ;
        RECT 4.400 288.640 35.600 290.040 ;
        RECT 0.525 286.640 36.000 288.640 ;
        RECT 4.400 285.240 35.600 286.640 ;
        RECT 0.525 283.240 36.000 285.240 ;
        RECT 4.400 281.840 36.000 283.240 ;
        RECT 0.525 279.840 36.000 281.840 ;
        RECT 4.400 278.440 35.600 279.840 ;
        RECT 0.525 276.440 36.000 278.440 ;
        RECT 4.400 275.040 36.000 276.440 ;
        RECT 0.525 273.040 36.000 275.040 ;
        RECT 4.400 271.640 35.600 273.040 ;
        RECT 0.525 269.640 36.000 271.640 ;
        RECT 4.400 268.240 36.000 269.640 ;
        RECT 0.525 266.240 36.000 268.240 ;
        RECT 4.400 264.840 35.600 266.240 ;
        RECT 0.525 262.840 36.000 264.840 ;
        RECT 4.400 261.440 36.000 262.840 ;
        RECT 0.525 259.440 36.000 261.440 ;
        RECT 4.400 258.040 36.000 259.440 ;
        RECT 0.525 256.040 36.000 258.040 ;
        RECT 4.400 254.640 35.600 256.040 ;
        RECT 0.525 252.640 36.000 254.640 ;
        RECT 4.400 251.240 36.000 252.640 ;
        RECT 0.525 249.240 36.000 251.240 ;
        RECT 4.400 247.840 35.600 249.240 ;
        RECT 0.525 245.840 36.000 247.840 ;
        RECT 4.400 244.440 36.000 245.840 ;
        RECT 0.525 242.440 36.000 244.440 ;
        RECT 4.400 241.040 36.000 242.440 ;
        RECT 0.525 239.040 36.000 241.040 ;
        RECT 4.400 237.640 35.600 239.040 ;
        RECT 0.525 235.640 36.000 237.640 ;
        RECT 4.400 234.240 36.000 235.640 ;
        RECT 0.525 232.240 36.000 234.240 ;
        RECT 4.400 230.840 35.600 232.240 ;
        RECT 0.525 228.840 36.000 230.840 ;
        RECT 4.400 227.440 36.000 228.840 ;
        RECT 0.525 225.440 36.000 227.440 ;
        RECT 4.400 224.040 35.600 225.440 ;
        RECT 0.525 222.040 36.000 224.040 ;
        RECT 4.400 220.640 35.600 222.040 ;
        RECT 0.525 218.640 36.000 220.640 ;
        RECT 4.400 217.240 35.600 218.640 ;
        RECT 0.525 215.240 36.000 217.240 ;
        RECT 4.400 213.840 35.600 215.240 ;
        RECT 0.525 211.840 36.000 213.840 ;
        RECT 4.400 210.440 35.600 211.840 ;
        RECT 0.525 208.440 36.000 210.440 ;
        RECT 4.400 207.040 35.600 208.440 ;
        RECT 0.525 205.040 36.000 207.040 ;
        RECT 4.400 203.640 35.600 205.040 ;
        RECT 0.525 201.640 36.000 203.640 ;
        RECT 4.400 200.240 35.600 201.640 ;
        RECT 0.525 198.240 36.000 200.240 ;
        RECT 4.400 196.840 36.000 198.240 ;
        RECT 0.525 194.840 36.000 196.840 ;
        RECT 0.525 193.440 35.600 194.840 ;
        RECT 0.525 191.440 36.000 193.440 ;
        RECT 4.400 190.040 35.600 191.440 ;
        RECT 0.525 188.040 36.000 190.040 ;
        RECT 4.400 186.640 36.000 188.040 ;
        RECT 0.525 184.640 36.000 186.640 ;
        RECT 4.400 183.240 35.600 184.640 ;
        RECT 0.525 181.240 36.000 183.240 ;
        RECT 4.400 179.840 36.000 181.240 ;
        RECT 0.525 177.840 36.000 179.840 ;
        RECT 4.400 176.440 35.600 177.840 ;
        RECT 0.525 174.440 36.000 176.440 ;
        RECT 4.400 173.040 36.000 174.440 ;
        RECT 0.525 171.040 36.000 173.040 ;
        RECT 4.400 169.640 35.600 171.040 ;
        RECT 0.525 167.640 36.000 169.640 ;
        RECT 4.400 166.240 35.600 167.640 ;
        RECT 0.525 164.240 36.000 166.240 ;
        RECT 4.400 162.840 35.600 164.240 ;
        RECT 0.525 160.840 36.000 162.840 ;
        RECT 4.400 159.440 35.600 160.840 ;
        RECT 0.525 157.440 36.000 159.440 ;
        RECT 4.400 156.040 35.600 157.440 ;
        RECT 0.525 154.040 36.000 156.040 ;
        RECT 4.400 152.640 35.600 154.040 ;
        RECT 0.525 150.640 36.000 152.640 ;
        RECT 4.400 149.240 35.600 150.640 ;
        RECT 0.525 147.240 36.000 149.240 ;
        RECT 4.400 145.840 35.600 147.240 ;
        RECT 0.525 143.840 36.000 145.840 ;
        RECT 4.400 142.440 35.600 143.840 ;
        RECT 0.525 140.440 36.000 142.440 ;
        RECT 0.525 139.040 35.600 140.440 ;
        RECT 0.525 137.040 36.000 139.040 ;
        RECT 4.400 135.640 35.600 137.040 ;
        RECT 0.525 133.640 36.000 135.640 ;
        RECT 4.400 132.240 35.600 133.640 ;
        RECT 0.525 130.240 36.000 132.240 ;
        RECT 0.525 128.840 35.600 130.240 ;
        RECT 0.525 126.840 36.000 128.840 ;
        RECT 0.525 125.440 35.600 126.840 ;
        RECT 0.525 123.440 36.000 125.440 ;
        RECT 0.525 122.040 35.600 123.440 ;
        RECT 0.525 120.040 36.000 122.040 ;
        RECT 4.400 118.640 35.600 120.040 ;
        RECT 0.525 116.640 36.000 118.640 ;
        RECT 4.400 115.240 36.000 116.640 ;
        RECT 0.525 109.840 36.000 115.240 ;
        RECT 4.400 108.440 35.600 109.840 ;
        RECT 0.525 106.440 36.000 108.440 ;
        RECT 0.525 105.040 35.600 106.440 ;
        RECT 0.525 103.040 36.000 105.040 ;
        RECT 4.400 101.640 36.000 103.040 ;
        RECT 0.525 96.240 36.000 101.640 ;
        RECT 4.400 94.840 35.600 96.240 ;
        RECT 0.525 92.840 36.000 94.840 ;
        RECT 4.400 91.440 35.600 92.840 ;
        RECT 0.525 89.440 36.000 91.440 ;
        RECT 0.525 88.040 35.600 89.440 ;
        RECT 0.525 86.040 36.000 88.040 ;
        RECT 0.525 84.640 35.600 86.040 ;
        RECT 0.525 82.640 36.000 84.640 ;
        RECT 4.400 81.240 36.000 82.640 ;
        RECT 0.525 79.240 36.000 81.240 ;
        RECT 4.400 77.840 35.600 79.240 ;
        RECT 0.525 72.440 36.000 77.840 ;
        RECT 4.400 71.040 36.000 72.440 ;
        RECT 0.525 69.040 36.000 71.040 ;
        RECT 4.400 67.640 36.000 69.040 ;
        RECT 0.525 65.640 36.000 67.640 ;
        RECT 4.400 64.240 35.600 65.640 ;
        RECT 0.525 62.240 36.000 64.240 ;
        RECT 0.525 60.840 35.600 62.240 ;
        RECT 0.525 58.840 36.000 60.840 ;
        RECT 0.525 57.440 35.600 58.840 ;
        RECT 0.525 55.440 36.000 57.440 ;
        RECT 4.400 54.040 35.600 55.440 ;
        RECT 0.525 52.040 36.000 54.040 ;
        RECT 0.525 50.640 35.600 52.040 ;
        RECT 0.525 48.640 36.000 50.640 ;
        RECT 4.400 47.240 35.600 48.640 ;
        RECT 0.525 45.240 36.000 47.240 ;
        RECT 0.525 43.840 35.600 45.240 ;
        RECT 0.525 41.840 36.000 43.840 ;
        RECT 4.400 40.440 36.000 41.840 ;
        RECT 0.525 38.440 36.000 40.440 ;
        RECT 0.525 37.040 35.600 38.440 ;
        RECT 0.525 35.040 36.000 37.040 ;
        RECT 4.400 33.640 35.600 35.040 ;
        RECT 0.525 31.640 36.000 33.640 ;
        RECT 4.400 30.240 36.000 31.640 ;
        RECT 0.525 28.240 36.000 30.240 ;
        RECT 0.525 26.840 35.600 28.240 ;
        RECT 0.525 24.840 36.000 26.840 ;
        RECT 0.525 23.440 35.600 24.840 ;
        RECT 0.525 21.440 36.000 23.440 ;
        RECT 4.400 20.040 36.000 21.440 ;
        RECT 0.525 18.040 36.000 20.040 ;
        RECT 4.400 16.640 36.000 18.040 ;
        RECT 0.525 10.715 36.000 16.640 ;
      LAYER met4 ;
        RECT 3.975 12.415 20.640 536.345 ;
        RECT 23.040 12.415 23.940 536.345 ;
        RECT 26.340 12.415 27.305 536.345 ;
  END
END add3x64
END LIBRARY

